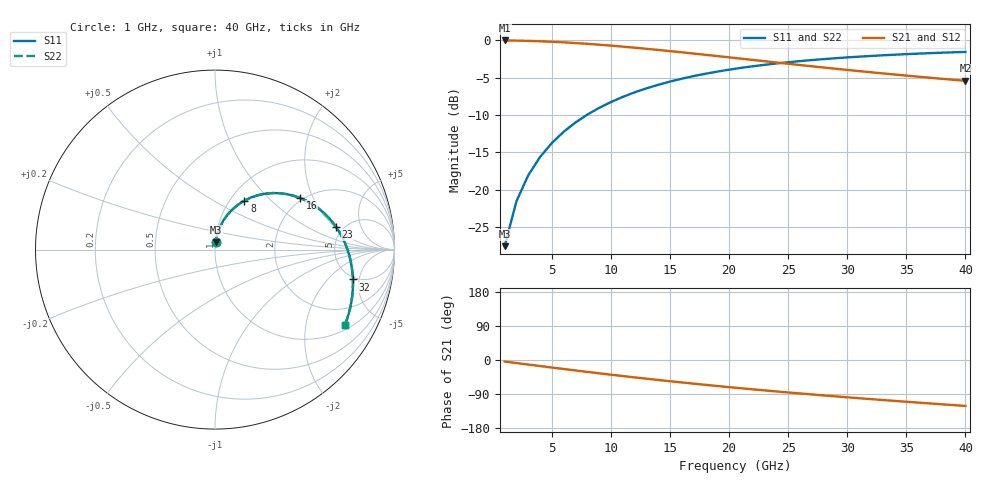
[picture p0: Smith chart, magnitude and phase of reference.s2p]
! circuitRF F0 spike reference -- case A, openEMS, PEC wire of true radius 12.7 um, dw 3.175 um
! openEMS probes -> S by postproc.py (own time column per probe); port 1 excited only;
! S22 = S11 and S12 = S21 by the mirror symmetry of the geometry (not a second run)
# GHz S RI R 50
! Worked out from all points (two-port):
!   40 points, 1 GHz to 40 GHz, reference 50 ohm
!   highest |S21| = -0.01 dB at 1 GHz (marker M1); lowest = -5.4 dB at 40 GHz (marker M2)
!   |S21| within 3 dB of the highest: start of sweep to 24.28 GHz
!   lowest |S11| = -27.6 dB at 1 GHz (marker M3), VSWR 1.09, Z = 50.2 + j4.19 ohm
!   |S11| at or under -10 dB: start of sweep to 7.949 GHz
!   |S22| runs from -27.6 to -1.5 dB; largest |S21 - S12| = 0
!   S11 on the Smith chart (normalised r, x): 1 GHz: 1.00, +0.08; 8 GHz: 1.16, +0.71; 16 GHz: 1.92, +1.60; 23 GHz: 4.33, +2.08; 32 GHz: 4.70, -4.09; 40 GHz: 1.18, -3.32
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1  0.00326 0.0417  0.9962 -0.0697  0.9962 -0.0697  0.00326 0.0417
2  0.0117 0.0827  0.9865 -0.1385  0.9865 -0.1385  0.0117 0.0827
3  0.0257 0.1221  0.9704 -0.2058  0.9704 -0.2058  0.0257 0.1221
4  0.0449 0.1593  0.9483 -0.2708  0.9483 -0.2708  0.0449 0.1593
5  0.0689 0.1935  0.9206 -0.3326  0.9206 -0.3326  0.0689 0.1935
6  0.0971 0.2241  0.8877 -0.3906  0.8877 -0.3906  0.0971 0.2241
7  0.129 0.2506  0.8504 -0.4444  0.8504 -0.4444  0.129 0.2506
8  0.1638 0.2728  0.8094 -0.4936  0.8094 -0.4936  0.1638 0.2728
9  0.2009 0.2903  0.7654 -0.5379  0.7654 -0.5379  0.2009 0.2903
11  0.2791 0.3114  0.671 -0.6117  0.671 -0.6117  0.2791 0.3114
14  0.3979 0.3094  0.5227 -0.6865  0.5227 -0.6865  0.3979 0.3094
16  0.4727 0.2884  0.4248 -0.7149  0.4248 -0.7149  0.4727 0.2884
18  0.541 0.2541  0.331 -0.7287  0.331 -0.7287  0.541 0.2541
21  0.6278 0.1836  0.2012 -0.7271  0.2012 -0.7271  0.6278 0.1836
23  0.6741 0.1271  0.1233 -0.7146  0.1233 -0.7146  0.6741 0.1271
25  0.7107 0.0655  0.0527 -0.6951  0.0527 -0.6951  0.7107 0.0655
27  0.738 0.000691  -0.0106 -0.6705  -0.0106 -0.6705  0.738 0.000691
29  0.7563 -0.0659  -0.067 -0.6422  -0.067 -0.6422  0.7563 -0.0659
32  0.7684 -0.1663  -0.1399 -0.5953  -0.1399 -0.5953  0.7684 -0.1663
34  0.767 -0.2325  -0.1815 -0.5621  -0.1815 -0.5621  0.767 -0.2325
37  0.7523 -0.3289  -0.2346 -0.5107  -0.2346 -0.5107  0.7523 -0.3289
40  0.7235 -0.4204  -0.2773 -0.4586  -0.2773 -0.4586  0.7235 -0.4204
